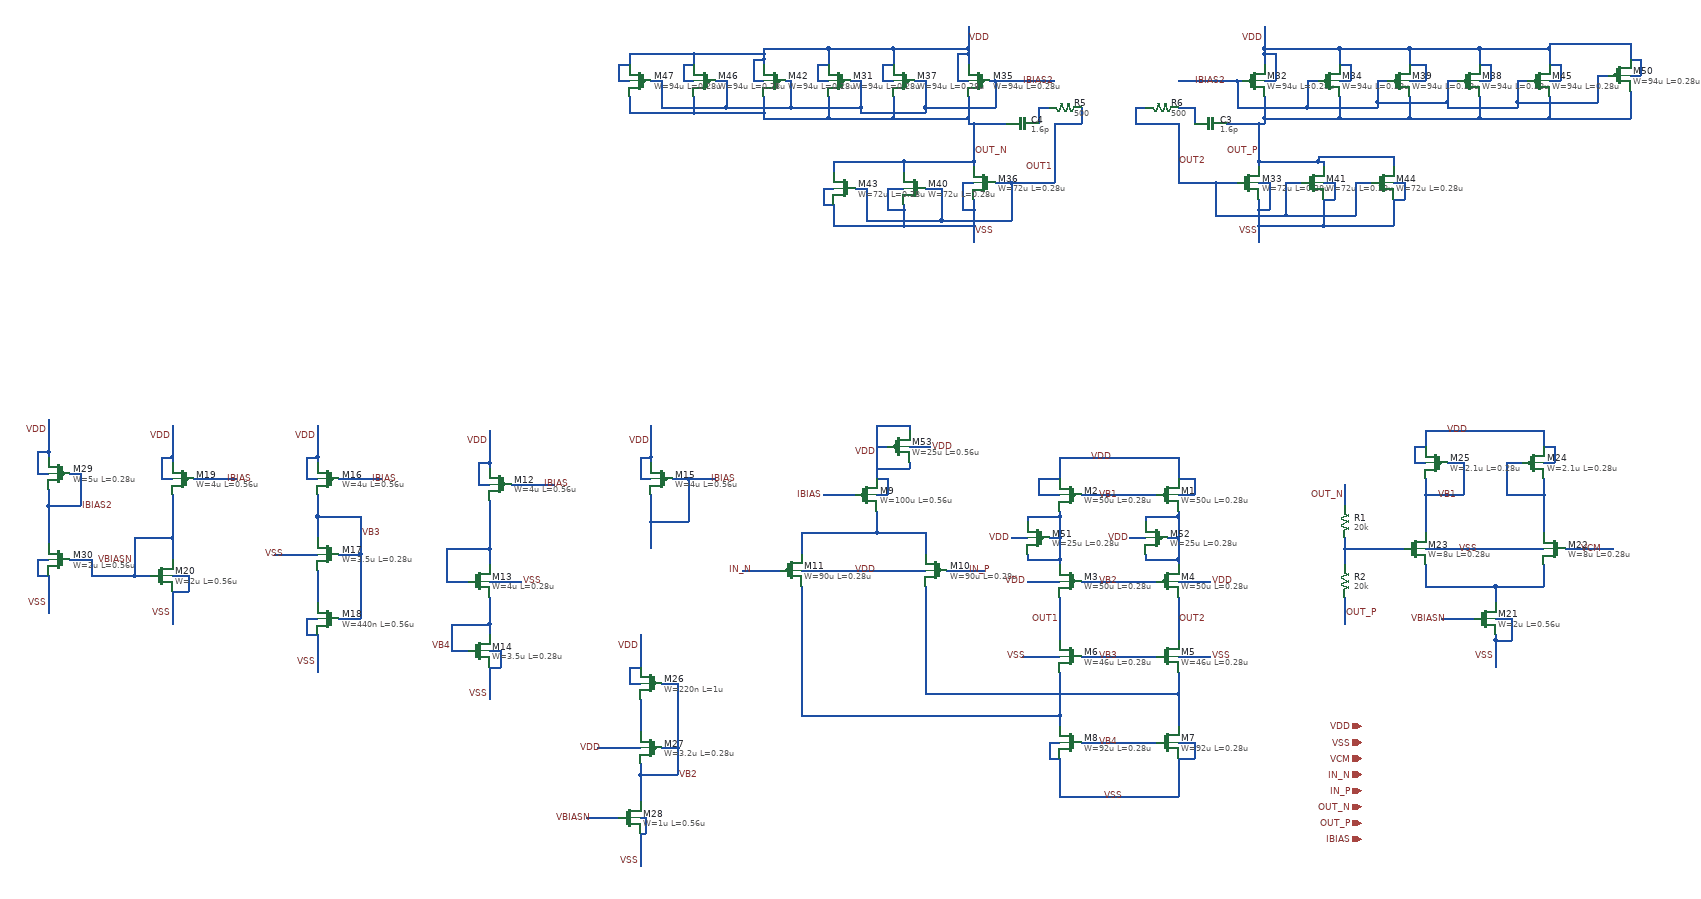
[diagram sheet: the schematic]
v {xschem version=3.1.0 file_version=1.2
}
G {}
K {}
V {}
S {}
E {}
N 80 -230 80 -190 {
lab=VDD}
N 80 -230 300 -230 {
lab=VDD}
N 300 -230 300 -190 {
lab=VDD}
N 300 -40 300 -30 {
lab=#net1}
N 80 -40 80 -30 {
lab=#net2}
N 120 -160 260 -160 {
lab=VB1}
N 120 0 260 0 {
lab=VB2}
N 80 250 80 270 {
lab=#net3}
N 300 210 300 270 {
lab=#net4}
N 80 330 80 400 {
lab=VSS}
N 80 400 300 400 {
lab=VSS}
N 300 330 300 400 {
lab=VSS}
N 120 300 260 300 {
lab=VB4}
N 120 140 260 140 {
lab=VB3}
N 300 140 360 140 {
lab=VSS}
N 300 300 330 300 {
lab=VSS}
N 330 300 330 330 {
lab=VSS}
N 300 330 330 330 {
lab=VSS}
N 10 140 80 140 {
lab=VSS}
N 60 300 80 300 {
lab=VSS}
N 60 300 60 330 {
lab=VSS}
N 60 330 80 330 {
lab=VSS}
N 300 0 360 0 {
lab=VDD}
N 300 -160 330 -160 {
lab=VDD}
N 330 -190 330 -160 {
lab=VDD}
N 300 -190 330 -190 {
lab=VDD}
N 40 -190 80 -190 {
lab=VDD}
N 40 -190 40 -160 {
lab=VDD}
N 40 -160 80 -160 {
lab=VDD}
N 20 0 80 0 {
lab=VDD}
N -400 -90 -400 -50 {
lab=#net5}
N -260 -90 -170 -90 {
lab=#net5}
N -170 -90 -170 -50 {
lab=#net5}
N -260 -130 -260 -90 {
lab=#net5}
N -260 -160 -240 -160 {
lab=VDD}
N -240 -190 -240 -160 {
lab=VDD}
N -260 -190 -240 -190 {
lab=VDD}
N -260 -290 -260 -190 {
lab=VDD}
N -360 -160 -300 -160 {
lab=IBIAS}
N -510 -20 -440 -20 {
lab=IN_N}
N -400 -20 -170 -20 {
lab=VDD}
N -170 210 300 210 {
lab=#net4}
N -400 170 -400 250 {
lab=#net3}
N -400 250 80 250 {
lab=#net3}
N -130 -20 -60 -20 {
lab=IN_P}
N -980 -220 -980 -210 {
lab=VDD}
N -1000 -180 -980 -180 {
lab=VDD}
N -1000 -220 -1000 -180 {
lab=VDD}
N -1000 -220 -980 -220 {
lab=VDD}
N -940 -180 -860 -180 {
lab=IBIAS}
N -980 -150 -980 -60 {
lab=#net6}
N -980 -60 -980 -30 {
lab=#net6}
N -980 0 -920 0 {
lab=VSS}
N -1060 0 -1020 0 {
lab=#net6}
N -1060 -60 -1060 0 {
lab=#net6}
N -1060 -60 -980 -60 {
lab=#net6}
N -980 80 -980 100 {
lab=VB4}
N -1050 130 -1020 130 {
lab=VB4}
N -1050 80 -1050 130 {
lab=VB4}
N -1050 80 -980 80 {
lab=VB4}
N -980 160 -980 220 {
lab=VSS}
N -980 130 -960 130 {
lab=VSS}
N -960 130 -960 160 {
lab=VSS}
N -980 160 -960 160 {
lab=VSS}
N -680 -230 -680 -220 {
lab=VDD}
N -700 -190 -680 -190 {
lab=VDD}
N -700 -230 -700 -190 {
lab=VDD}
N -700 -230 -680 -230 {
lab=VDD}
N -610 -190 -560 -190 {
lab=IBIAS}
N -680 -160 -680 -110 {
lab=IBIAS}
N -680 -110 -610 -110 {
lab=IBIAS}
N -610 -190 -610 -110 {
lab=IBIAS}
N -680 -110 -680 -60 {
lab=IBIAS}
N -1300 -230 -1300 -220 {
lab=VDD}
N -1320 -190 -1300 -190 {
lab=VDD}
N -1320 -230 -1320 -190 {
lab=VDD}
N -1320 -230 -1300 -230 {
lab=VDD}
N -1260 -190 -1180 -190 {
lab=IBIAS}
N -1300 100 -1300 170 {
lab=VSS}
N -1260 70 -1220 70 {
lab=VB3}
N -1300 -20 -1300 40 {
lab=#net7}
N -1260 -50 -1220 -50 {
lab=VB3}
N -1220 -50 -1220 70 {
lab=VB3}
N -1220 -120 -1220 -50 {
lab=VB3}
N -1300 -120 -1220 -120 {
lab=VB3}
N -1300 -160 -1300 -120 {
lab=VB3}
N -1300 -120 -1300 -80 {
lab=VB3}
N -1380 -50 -1300 -50 {
lab=VSS}
N -1320 70 -1300 70 {
lab=VSS}
N -1320 70 -1320 100 {
lab=VSS}
N -1320 100 -1300 100 {
lab=VSS}
N -1570 -230 -1570 -220 {
lab=VDD}
N -1590 -190 -1570 -190 {
lab=VDD}
N -1590 -230 -1590 -190 {
lab=VDD}
N -1590 -230 -1570 -230 {
lab=VDD}
N -1530 -190 -1450 -190 {
lab=IBIAS}
N -1570 -80 -1570 -40 {
lab=VBIASN}
N -1570 20 -1570 80 {
lab=VSS}
N -1570 -10 -1540 -10 {
lab=VSS}
N -1540 -10 -1540 20 {
lab=VSS}
N -1570 20 -1540 20 {
lab=VSS}
N -1640 -10 -1610 -10 {
lab=VBIASN}
N -1640 -80 -1640 -10 {
lab=VBIASN}
N -1640 -80 -1570 -80 {
lab=VBIASN}
N 760 -280 760 -250 {
lab=VDD}
N 760 -280 980 -280 {
lab=VDD}
N 980 -280 980 -250 {
lab=VDD}
N 980 -160 980 -90 {
lab=#net8}
N 760 -160 760 -90 {
lab=VB1}
N 800 -220 830 -220 {
lab=VB1}
N 830 -220 830 -160 {
lab=VB1}
N 760 -160 830 -160 {
lab=VB1}
N 910 -220 940 -220 {
lab=#net8}
N 910 -220 910 -160 {
lab=#net8}
N 910 -160 980 -160 {
lab=#net8}
N 980 -30 980 10 {
lab=#net9}
N 890 10 980 10 {
lab=#net9}
N 760 -30 760 10 {
lab=#net9}
N 890 10 890 40 {
lab=#net9}
N 890 110 890 160 {
lab=VSS}
N 790 70 850 70 {
lab=VBIASN}
N 610 -180 610 -140 {
lab=OUT_N}
N 610 -60 610 -30 {
lab=#net10}
N 610 30 610 80 {
lab=OUT_P}
N 610 -60 720 -60 {
lab=#net10}
N 1020 -60 1110 -60 {
lab=VCM}
N -700 360 -700 410 {
lab=VB2}
N -700 440 -690 440 {
lab=VSS}
N -690 440 -690 470 {
lab=VSS}
N -700 470 -690 470 {
lab=VSS}
N -700 470 -700 530 {
lab=VSS}
N -800 440 -740 440 {
lab=VBIASN}
N -700 220 -700 280 {
lab=#net11}
N -780 310 -700 310 {
lab=VDD}
N -700 100 -700 160 {
lab=VDD}
N -660 190 -630 190 {
lab=VB2}
N -630 310 -630 360 {
lab=VB2}
N -700 360 -630 360 {
lab=VB2}
N -660 310 -630 310 {
lab=VB2}
N -720 190 -700 190 {
lab=VDD}
N -720 160 -720 190 {
lab=VDD}
N -720 160 -700 160 {
lab=VDD}
N 740 -220 760 -220 {
lab=VDD}
N 740 -250 740 -220 {
lab=VDD}
N 740 -250 760 -250 {
lab=VDD}
N 980 -220 1000 -220 {
lab=VDD}
N 1000 -250 1000 -220 {
lab=VDD}
N 980 -250 1000 -250 {
lab=VDD}
N 760 -60 980 -60 {
lab=VSS}
N 890 70 920 70 {
lab=VSS}
N 920 70 920 110 {
lab=VSS}
N 890 110 920 110 {
lab=VSS}
N -1800 -240 -1800 -230 {
lab=VDD}
N -1820 -200 -1800 -200 {
lab=VDD}
N -1820 -240 -1820 -200 {
lab=VDD}
N -1820 -240 -1800 -240 {
lab=VDD}
N -1800 -10 -1800 60 {
lab=VSS}
N -1820 -40 -1800 -40 {
lab=VSS}
N -1820 -40 -1820 -10 {
lab=VSS}
N -1820 -10 -1800 -10 {
lab=VSS}
N -1760 -40 -1720 -40 {
lab=VBIASN}
N -1720 -40 -1720 -10 {
lab=VBIASN}
N -1720 -10 -1640 -10 {
lab=VBIASN}
N -1800 -140 -1800 -70 {
lab=IBIAS2}
N -1760 -200 -1740 -200 {
lab=IBIAS2}
N -1740 -200 -1740 -140 {
lab=IBIAS2}
N -1800 -140 -1740 -140 {
lab=IBIAS2}
N 460 -980 460 -960 {
lab=VDD}
N 460 -930 480 -930 {
lab=VDD}
N 480 -980 480 -930 {
lab=VDD}
N 460 -980 480 -980 {
lab=VDD}
N 410 -930 420 -930 {
lab=IBIAS2}
N 450 -850 460 -850 {
lab=OUT_P}
N 460 -860 460 -850 {
lab=OUT_P}
N 450 -780 450 -770 {
lab=OUT_P}
N 450 -660 450 -630 {
lab=VSS}
N 450 -740 470 -740 {
lab=VSS}
N 470 -740 470 -690 {
lab=VSS}
N 450 -690 470 -690 {
lab=VSS}
N 300 -850 300 -740 {
lab=OUT2}
N 370 -740 410 -740 {
lab=OUT2}
N 540 -930 560 -930 {
lab=IBIAS2}
N 540 -930 540 -880 {
lab=IBIAS2}
N 410 -880 540 -880 {
lab=IBIAS2}
N 410 -930 410 -880 {
lab=IBIAS2}
N 600 -990 600 -960 {
lab=VDD}
N 460 -990 600 -990 {
lab=VDD}
N 600 -930 620 -930 {
lab=VDD}
N 620 -960 620 -930 {
lab=VDD}
N 600 -960 620 -960 {
lab=VDD}
N 600 -900 600 -860 {
lab=OUT_P}
N 460 -860 600 -860 {
lab=OUT_P}
N -90 -980 -90 -960 {
lab=VDD}
N -110 -930 -90 -930 {
lab=VDD}
N -110 -980 -110 -930 {
lab=VDD}
N -110 -980 -90 -980 {
lab=VDD}
N -40 -930 70 -930 {
lab=IBIAS2}
N -80 -850 -20 -850 {
lab=OUT_N}
N -90 -860 -90 -850 {
lab=OUT_N}
N -80 -780 -80 -770 {
lab=OUT_N}
N -80 -660 -80 -630 {
lab=VSS}
N -100 -740 -80 -740 {
lab=VSS}
N -100 -740 -100 -690 {
lab=VSS}
N -100 -690 -80 -690 {
lab=VSS}
N 70 -850 70 -740 {
lab=OUT1}
N -10 -740 70 -740 {
lab=OUT1}
N -190 -930 -170 -930 {
lab=IBIAS2}
N -170 -930 -170 -880 {
lab=IBIAS2}
N -170 -880 -40 -880 {
lab=IBIAS2}
N -40 -930 -40 -880 {
lab=IBIAS2}
N -230 -990 -230 -960 {
lab=VDD}
N -250 -930 -230 -930 {
lab=VDD}
N -250 -960 -250 -930 {
lab=VDD}
N -250 -960 -230 -960 {
lab=VDD}
N -230 -900 -230 -860 {
lab=OUT_N}
N -230 -860 -90 -860 {
lab=OUT_N}
N 220 -880 240 -880 {
lab=OUT2}
N 220 -880 220 -850 {
lab=OUT2}
N 220 -850 300 -850 {
lab=OUT2}
N 330 -880 330 -850 {
lab=#net12}
N 300 -880 330 -880 {
lab=#net12}
N 120 -880 120 -850 {
lab=OUT1}
N 70 -850 120 -850 {
lab=OUT1}
N 40 -880 40 -850 {
lab=#net13}
N 40 -880 60 -880 {
lab=#net13}
N 730 -990 730 -960 {
lab=VDD}
N 600 -990 730 -990 {
lab=VDD}
N 730 -900 730 -860 {
lab=OUT_P}
N 600 -860 730 -860 {
lab=OUT_P}
N 670 -930 690 -930 {
lab=IBIAS2}
N 670 -890 670 -880 {
lab=IBIAS2}
N 540 -880 670 -880 {
lab=IBIAS2}
N 730 -930 760 -930 {
lab=VDD}
N 760 -960 760 -930 {
lab=VDD}
N 730 -960 760 -960 {
lab=VDD}
N -310 -930 -290 -930 {
lab=IBIAS2}
N -290 -880 -290 -870 {
lab=IBIAS2}
N -290 -870 -170 -870 {
lab=IBIAS2}
N -170 -880 -170 -870 {
lab=IBIAS2}
N -350 -990 -350 -960 {
lab=VDD}
N -230 -990 -90 -990 {
lab=VDD}
N -370 -930 -350 -930 {
lab=VDD}
N -370 -960 -370 -930 {
lab=VDD}
N -370 -960 -350 -960 {
lab=VDD}
N -350 -900 -350 -860 {
lab=OUT_N}
N -350 -860 -230 -860 {
lab=OUT_N}
N 500 -740 530 -740 {
lab=OUT2}
N 500 -740 500 -680 {
lab=OUT2}
N 370 -680 500 -680 {
lab=OUT2}
N 370 -740 370 -680 {
lab=OUT2}
N 570 -780 570 -770 {
lab=OUT_P}
N 560 -780 570 -780 {
lab=OUT_P}
N 570 -710 570 -660 {
lab=VSS}
N 450 -660 570 -660 {
lab=VSS}
N 570 -740 590 -740 {
lab=VSS}
N 590 -740 590 -710 {
lab=VSS}
N 570 -710 590 -710 {
lab=VSS}
N -210 -780 -210 -760 {
lab=OUT_N}
N -210 -780 -80 -780 {
lab=OUT_N}
N -210 -690 -210 -660 {
lab=VSS}
N -210 -660 -80 -660 {
lab=VSS}
N -170 -730 -140 -730 {
lab=OUT1}
N -140 -730 -140 -670 {
lab=OUT1}
N -140 -670 -10 -670 {
lab=OUT1}
N -10 -740 -10 -670 {
lab=OUT1}
N -240 -730 -210 -730 {
lab=VSS}
N -240 -730 -240 -690 {
lab=VSS}
N -240 -690 -210 -690 {
lab=VSS}
N -470 -970 -470 -960 {
lab=VDD}
N -470 -990 -350 -990 {
lab=VDD}
N -470 -870 -470 -860 {
lab=OUT_N}
N -470 -860 -350 -860 {
lab=OUT_N}
N -490 -930 -470 -930 {
lab=VDD}
N -490 -970 -490 -930 {
lab=VDD}
N -490 -970 -470 -970 {
lab=VDD}
N -430 -930 -420 -930 {
lab=IBIAS2}
N -420 -930 -420 -880 {
lab=IBIAS2}
N -420 -880 -290 -880 {
lab=IBIAS2}
N 860 -990 860 -960 {
lab=VDD}
N 730 -990 860 -990 {
lab=VDD}
N 860 -930 880 -930 {
lab=VDD}
N 880 -960 880 -930 {
lab=VDD}
N 860 -960 880 -960 {
lab=VDD}
N 800 -930 820 -930 {
lab=IBIAS2}
N 800 -930 800 -890 {
lab=IBIAS2}
N 670 -890 800 -890 {
lab=IBIAS2}
N 860 -900 860 -860 {
lab=OUT_P}
N 730 -860 860 -860 {
lab=OUT_P}
N 700 -790 700 -770 {
lab=OUT_P}
N 560 -790 700 -790 {
lab=OUT_P}
N 560 -790 560 -780 {
lab=OUT_P}
N 630 -740 660 -740 {
lab=OUT2}
N 630 -740 630 -680 {
lab=OUT2}
N 500 -680 630 -680 {
lab=OUT2}
N 570 -660 700 -660 {
lab=VSS}
N 700 -710 700 -660 {
lab=VSS}
N 700 -740 720 -740 {
lab=VSS}
N 720 -740 720 -710 {
lab=VSS}
N 700 -710 720 -710 {
lab=VSS}
N -340 -780 -340 -760 {
lab=OUT_N}
N -340 -780 -210 -780 {
lab=OUT_N}
N -340 -700 -340 -660 {
lab=VSS}
N -340 -660 -210 -660 {
lab=VSS}
N -360 -730 -340 -730 {
lab=VSS}
N -360 -730 -360 -700 {
lab=VSS}
N -360 -700 -340 -700 {
lab=VSS}
N -300 -730 -280 -730 {
lab=OUT1}
N -280 -730 -280 -670 {
lab=OUT1}
N -280 -670 -140 -670 {
lab=OUT1}
N 990 -990 990 -960 {
lab=VDD}
N 860 -990 990 -990 {
lab=VDD}
N 860 -860 990 -860 {
lab=OUT_P}
N 990 -900 990 -860 {
lab=OUT_P}
N 990 -930 1010 -930 {
lab=VDD}
N 1010 -960 1010 -930 {
lab=VDD}
N 990 -960 1010 -960 {
lab=VDD}
N 930 -930 950 -930 {
lab=IBIAS2}
N 930 -890 930 -880 {
lab=IBIAS2}
N 800 -880 930 -880 {
lab=IBIAS2}
N 800 -890 800 -880 {
lab=IBIAS2}
N -600 -980 -600 -960 {
lab=VDD}
N -600 -980 -470 -980 {
lab=VDD}
N -600 -900 -600 -870 {
lab=OUT_N}
N -600 -870 -470 -870 {
lab=OUT_N}
N -540 -880 -420 -880 {
lab=IBIAS2}
N -540 -930 -540 -880 {
lab=IBIAS2}
N -560 -930 -540 -930 {
lab=IBIAS2}
N -620 -930 -600 -930 {
lab=VDD}
N -620 -960 -620 -930 {
lab=VDD}
N -620 -960 -600 -960 {
lab=VDD}
N 1140 -1000 1140 -970 {
lab=VDD}
N 1140 -910 1140 -860 {
lab=OUT_P}
N 1140 -940 1160 -940 {
lab=VDD}
N 1160 -970 1160 -940 {
lab=VDD}
N 1140 -970 1160 -970 {
lab=VDD}
N 1080 -940 1100 -940 {
lab=IBIAS2}
N 1080 -940 1080 -890 {
lab=IBIAS2}
N -720 -980 -720 -960 {
lab=VDD}
N -720 -900 -720 -870 {
lab=OUT_N}
N -660 -930 -660 -880 {
lab=IBIAS2}
N -680 -930 -660 -930 {
lab=IBIAS2}
N -740 -930 -720 -930 {
lab=VDD}
N -740 -960 -740 -930 {
lab=VDD}
N -740 -960 -720 -960 {
lab=VDD}
N -660 -880 -540 -880 {
lab=IBIAS2}
N -720 -870 -600 -870 {
lab=OUT_N}
N -720 -980 -600 -980 {
lab=VDD}
N 990 -1000 1140 -1000 {
lab=VDD}
N 990 -1000 990 -990 {
lab=VDD}
N 990 -860 1140 -860 {
lab=OUT_P}
N 930 -890 1080 -890 {
lab=IBIAS2}
N 60 -80 80 -80 {
lab=#net2}
N 20 -120 20 -110 {
lab=#net2}
N 20 -120 80 -120 {
lab=#net2}
N 20 -50 20 -40 {
lab=#net2}
N 20 -40 80 -40 {
lab=#net2}
N -10 -80 20 -80 {
lab=VDD}
N 280 -80 300 -80 {
lab=#net1}
N 240 -120 240 -110 {
lab=#net1}
N 240 -120 300 -120 {
lab=#net1}
N 240 -50 240 -40 {
lab=#net1}
N 240 -40 300 -40 {
lab=#net1}
N 210 -80 240 -80 {
lab=VDD}
N -400 -90 -260 -90 {
lab=#net5}
N 300 170 300 210 {
lab=#net4}
N 80 170 80 250 {
lab=#net3}
N -980 -280 -980 -220 {
lab=VDD}
N -980 30 -980 80 {
lab=VB4}
N -680 -290 -680 -230 {
lab=VDD}
N -640 -190 -610 -190 {
lab=IBIAS}
N -1300 -290 -1300 -230 {
lab=VDD}
N -1570 -290 -1570 -230 {
lab=VDD}
N -1570 -160 -1570 -80 {
lab=VBIASN}
N 760 -190 760 -160 {
lab=VB1}
N 980 -190 980 -160 {
lab=#net8}
N 760 10 890 10 {
lab=#net9}
N 610 -80 610 -60 {
lab=#net10}
N -700 340 -700 360 {
lab=VB2}
N -630 190 -630 310 {
lab=VB2}
N 890 100 890 110 {
lab=VSS}
N -1800 -300 -1800 -240 {
lab=VDD}
N -1800 -170 -1800 -140 {
lab=IBIAS2}
N 460 -990 460 -980 {
lab=VDD}
N 390 -850 450 -850 {
lab=OUT_P}
N 450 -710 450 -690 {
lab=VSS}
N 300 -930 410 -930 {
lab=IBIAS2}
N 460 -1030 460 -990 {
lab=VDD}
N 460 -900 460 -860 {
lab=OUT_P}
N -90 -990 -90 -980 {
lab=VDD}
N -90 -850 -80 -850 {
lab=OUT_N}
N -80 -710 -80 -690 {
lab=VSS}
N -50 -930 -40 -930 {
lab=IBIAS2}
N -350 -990 -230 -990 {
lab=VDD}
N -90 -1030 -90 -990 {
lab=VDD}
N -90 -900 -90 -860 {
lab=OUT_N}
N 300 -740 370 -740 {
lab=OUT2}
N 450 -850 450 -780 {
lab=OUT_P}
N 450 -690 450 -660 {
lab=VSS}
N -80 -850 -80 -780 {
lab=OUT_N}
N -80 -690 -80 -660 {
lab=VSS}
N -40 -740 -10 -740 {
lab=OUT1}
N -210 -700 -210 -690 {
lab=VSS}
N -470 -980 -470 -970 {
lab=VDD}
N -290 -930 -290 -880 {
lab=IBIAS2}
N 670 -930 670 -890 {
lab=IBIAS2}
N 450 -780 560 -780 {
lab=OUT_P}
N -470 -990 -470 -980 {
lab=VDD}
N -470 -900 -470 -870 {
lab=OUT_N}
N 930 -930 930 -890 {
lab=IBIAS2}
N -400 10 -400 90 {
lab=#net3}
N -170 10 -170 90 {
lab=#net4}
N -170 170 -170 210 {
lab=#net4}
N 80 -120 80 -80 {
lab=#net2}
N 80 -130 80 -120 {
lab=#net2}
N 80 -80 80 -40 {
lab=#net2}
N 300 -120 300 -80 {
lab=#net1}
N 300 -130 300 -120 {
lab=#net1}
N 300 -80 300 -40 {
lab=#net1}
N -200 -290 -200 -280 {
lab=VDD}
N -200 -220 -200 -210 {
lab=VDD}
N -200 -250 -160 -250 {
lab=VDD}
N -260 -250 -240 -250 {
lab=VDD}
N -260 -210 -200 -210 {
lab=VDD}
N -260 -290 -200 -290 {
lab=VDD}
N -400 90 -400 170 {
lab=#net3}
N -170 90 -170 170 {
lab=#net4}
N 300 30 300 110 {
lab=#net14}
N 80 30 80 110 {
lab=OUT1}
C {symbols/pfet_03v3.sym} 280 -160 0 0 {name=M1
L=0.28u
W=50u
nf=1
m=1
ad="'int((nf+1)/2) * W/nf * 0.18u'"
pd="'2*int((nf+1)/2) * (W/nf + 0.18u)'"
as="'int((nf+2)/2) * W/nf * 0.18u'"
ps="'2*int((nf+2)/2) * (W/nf + 0.18u)'"
nrd="'0.18u / W'" nrs="'0.18u / W'"
sa=0 sb=0 sd=0
model=pfet_03v3
spiceprefix=X
}
C {symbols/pfet_03v3.sym} 100 -160 0 1 {name=M2
L=0.28u
W=50u
nf=1
m=1
ad="'int((nf+1)/2) * W/nf * 0.18u'"
pd="'2*int((nf+1)/2) * (W/nf + 0.18u)'"
as="'int((nf+2)/2) * W/nf * 0.18u'"
ps="'2*int((nf+2)/2) * (W/nf + 0.18u)'"
nrd="'0.18u / W'" nrs="'0.18u / W'"
sa=0 sb=0 sd=0
model=pfet_03v3
spiceprefix=X
}
C {symbols/pfet_03v3.sym} 100 0 0 1 {name=M3
L=0.28u
W=50u
nf=1
m=1
ad="'int((nf+1)/2) * W/nf * 0.18u'"
pd="'2*int((nf+1)/2) * (W/nf + 0.18u)'"
as="'int((nf+2)/2) * W/nf * 0.18u'"
ps="'2*int((nf+2)/2) * (W/nf + 0.18u)'"
nrd="'0.18u / W'" nrs="'0.18u / W'"
sa=0 sb=0 sd=0
model=pfet_03v3
spiceprefix=X
}
C {symbols/pfet_03v3.sym} 280 0 0 0 {name=M4
L=0.28u
W=50u
nf=1
m=1
ad="'int((nf+1)/2) * W/nf * 0.18u'"
pd="'2*int((nf+1)/2) * (W/nf + 0.18u)'"
as="'int((nf+2)/2) * W/nf * 0.18u'"
ps="'2*int((nf+2)/2) * (W/nf + 0.18u)'"
nrd="'0.18u / W'" nrs="'0.18u / W'"
sa=0 sb=0 sd=0
model=pfet_03v3
spiceprefix=X
}
C {symbols/nfet_03v3.sym} 280 140 0 0 {name=M5
L=0.28u
W=46u
nf=1
m=1
ad="'int((nf+1)/2) * W/nf * 0.18u'"
pd="'2*int((nf+1)/2) * (W/nf + 0.18u)'"
as="'int((nf+2)/2) * W/nf * 0.18u'"
ps="'2*int((nf+2)/2) * (W/nf + 0.18u)'"
nrd="'0.18u / W'" nrs="'0.18u / W'"
sa=0 sb=0 sd=0
model=nfet_03v3
spiceprefix=X
}
C {symbols/nfet_03v3.sym} 100 140 0 1 {name=M6
L=0.28u
W=46u
nf=1
m=1
ad="'int((nf+1)/2) * W/nf * 0.18u'"
pd="'2*int((nf+1)/2) * (W/nf + 0.18u)'"
as="'int((nf+2)/2) * W/nf * 0.18u'"
ps="'2*int((nf+2)/2) * (W/nf + 0.18u)'"
nrd="'0.18u / W'" nrs="'0.18u / W'"
sa=0 sb=0 sd=0
model=nfet_03v3
spiceprefix=X
}
C {symbols/nfet_03v3.sym} 280 300 0 0 {name=M7
L=0.28u
W=92u
nf=1
m=1
ad="'int((nf+1)/2) * W/nf * 0.18u'"
pd="'2*int((nf+1)/2) * (W/nf + 0.18u)'"
as="'int((nf+2)/2) * W/nf * 0.18u'"
ps="'2*int((nf+2)/2) * (W/nf + 0.18u)'"
nrd="'0.18u / W'" nrs="'0.18u / W'"
sa=0 sb=0 sd=0
model=nfet_03v3
spiceprefix=X
}
C {symbols/nfet_03v3.sym} 100 300 0 1 {name=M8
L=0.28u
W=92u
nf=1
m=1
ad="'int((nf+1)/2) * W/nf * 0.18u'"
pd="'2*int((nf+1)/2) * (W/nf + 0.18u)'"
as="'int((nf+2)/2) * W/nf * 0.18u'"
ps="'2*int((nf+2)/2) * (W/nf + 0.18u)'"
nrd="'0.18u / W'" nrs="'0.18u / W'"
sa=0 sb=0 sd=0
model=nfet_03v3
spiceprefix=X
}
C {symbols/pfet_03v3.sym} -280 -160 0 0 {name=M9
L=0.56u
W=100u
nf=1
m=1
ad="'int((nf+1)/2) * W/nf * 0.18u'"
pd="'2*int((nf+1)/2) * (W/nf + 0.18u)'"
as="'int((nf+2)/2) * W/nf * 0.18u'"
ps="'2*int((nf+2)/2) * (W/nf + 0.18u)'"
nrd="'0.18u / W'" nrs="'0.18u / W'"
sa=0 sb=0 sd=0
model=pfet_03v3
spiceprefix=X
}
C {symbols/pfet_03v3.sym} -150 -20 0 1 {name=M10
L=0.28u
W=90u
nf=1
m=1
ad="'int((nf+1)/2) * W/nf * 0.18u'"
pd="'2*int((nf+1)/2) * (W/nf + 0.18u)'"
as="'int((nf+2)/2) * W/nf * 0.18u'"
ps="'2*int((nf+2)/2) * (W/nf + 0.18u)'"
nrd="'0.18u / W'" nrs="'0.18u / W'"
sa=0 sb=0 sd=0
model=pfet_03v3
spiceprefix=X
}
C {symbols/pfet_03v3.sym} -420 -20 0 0 {name=M11
L=0.28u
W=90u
nf=1
m=1
ad="'int((nf+1)/2) * W/nf * 0.18u'"
pd="'2*int((nf+1)/2) * (W/nf + 0.18u)'"
as="'int((nf+2)/2) * W/nf * 0.18u'"
ps="'2*int((nf+2)/2) * (W/nf + 0.18u)'"
nrd="'0.18u / W'" nrs="'0.18u / W'"
sa=0 sb=0 sd=0
model=pfet_03v3
spiceprefix=X
}
C {devices/lab_wire.sym} 180 -230 0 0 {name=p1 sig_type=std_logic lab=VDD}
C {devices/lab_wire.sym} -260 -240 0 0 {name=p2 sig_type=std_logic lab=VDD}
C {devices/lab_wire.sym} -260 -20 0 0 {name=p3 sig_type=std_logic lab=VDD}
C {devices/lab_wire.sym} 20 0 0 0 {name=p4 sig_type=std_logic lab=VDD}
C {devices/lab_wire.sym} 360 0 0 1 {name=p5 sig_type=std_logic lab=VDD}
C {devices/lab_wire.sym} 200 400 0 0 {name=p6 sig_type=std_logic lab=VSS}
C {devices/lab_wire.sym} 20 140 0 0 {name=p7 sig_type=std_logic lab=VSS}
C {devices/lab_wire.sym} 360 140 0 1 {name=p8 sig_type=std_logic lab=VSS}
C {symbols/pfet_03v3.sym} -960 -180 0 1 {name=M12
L=0.56u
W=4u
nf=1
m=1
ad="'int((nf+1)/2) * W/nf * 0.18u'"
pd="'2*int((nf+1)/2) * (W/nf + 0.18u)'"
as="'int((nf+2)/2) * W/nf * 0.18u'"
ps="'2*int((nf+2)/2) * (W/nf + 0.18u)'"
nrd="'0.18u / W'" nrs="'0.18u / W'"
sa=0 sb=0 sd=0
model=pfet_03v3
spiceprefix=X
}
C {symbols/nfet_03v3.sym} -1000 0 0 0 {name=M13
L=0.28u
W=4u
nf=1
m=1
ad="'int((nf+1)/2) * W/nf * 0.18u'"
pd="'2*int((nf+1)/2) * (W/nf + 0.18u)'"
as="'int((nf+2)/2) * W/nf * 0.18u'"
ps="'2*int((nf+2)/2) * (W/nf + 0.18u)'"
nrd="'0.18u / W'" nrs="'0.18u / W'"
sa=0 sb=0 sd=0
model=nfet_03v3
spiceprefix=X
}
C {symbols/nfet_03v3.sym} -1000 130 0 0 {name=M14
L=0.28u
W=3.5u
nf=1
m=1
ad="'int((nf+1)/2) * W/nf * 0.18u'"
pd="'2*int((nf+1)/2) * (W/nf + 0.18u)'"
as="'int((nf+2)/2) * W/nf * 0.18u'"
ps="'2*int((nf+2)/2) * (W/nf + 0.18u)'"
nrd="'0.18u / W'" nrs="'0.18u / W'"
sa=0 sb=0 sd=0
model=nfet_03v3
spiceprefix=X
}
C {devices/lab_wire.sym} -980 210 0 0 {name=p9 sig_type=std_logic lab=VSS}
C {symbols/pfet_03v3.sym} -660 -190 0 1 {name=M15
L=0.56u
W=4u
nf=1
m=1
ad="'int((nf+1)/2) * W/nf * 0.18u'"
pd="'2*int((nf+1)/2) * (W/nf + 0.18u)'"
as="'int((nf+2)/2) * W/nf * 0.18u'"
ps="'2*int((nf+2)/2) * (W/nf + 0.18u)'"
nrd="'0.18u / W'" nrs="'0.18u / W'"
sa=0 sb=0 sd=0
model=pfet_03v3
spiceprefix=X
}
C {devices/lab_wire.sym} -680 -260 0 0 {name=p10 sig_type=std_logic lab=VDD}
C {devices/lab_wire.sym} -980 -260 0 0 {name=p11 sig_type=std_logic lab=VDD}
C {devices/lab_wire.sym} -920 0 0 1 {name=p12 sig_type=std_logic lab=VSS}
C {devices/lab_wire.sym} -570 -190 0 1 {name=p14 sig_type=std_logic lab=IBIAS}
C {devices/lab_wire.sym} -880 -180 0 1 {name=p15 sig_type=std_logic lab=IBIAS}
C {devices/lab_wire.sym} -360 -160 0 0 {name=p16 sig_type=std_logic lab=IBIAS}
C {devices/lab_wire.sym} -490 -20 0 0 {name=p17 sig_type=std_logic lab=IN_N}
C {devices/lab_wire.sym} -90 -20 0 1 {name=p18 sig_type=std_logic lab=IN_P}
C {devices/lab_wire.sym} 190 -160 0 0 {name=p19 sig_type=std_logic lab=VB1}
C {devices/lab_wire.sym} 190 0 0 0 {name=p20 sig_type=std_logic lab=VB2}
C {devices/lab_wire.sym} 190 140 0 0 {name=p21 sig_type=std_logic lab=VB3}
C {devices/lab_wire.sym} 190 300 0 0 {name=p22 sig_type=std_logic lab=VB4}
C {devices/lab_wire.sym} -1050 120 0 0 {name=p23 sig_type=std_logic lab=VB4}
C {symbols/pfet_03v3.sym} -1280 -190 0 1 {name=M16
L=0.56u
W=4u
nf=1
m=1
ad="'int((nf+1)/2) * W/nf * 0.18u'"
pd="'2*int((nf+1)/2) * (W/nf + 0.18u)'"
as="'int((nf+2)/2) * W/nf * 0.18u'"
ps="'2*int((nf+2)/2) * (W/nf + 0.18u)'"
nrd="'0.18u / W'" nrs="'0.18u / W'"
sa=0 sb=0 sd=0
model=pfet_03v3
spiceprefix=X
}
C {devices/lab_wire.sym} -1300 -270 0 0 {name=p24 sig_type=std_logic lab=VDD}
C {devices/lab_wire.sym} -1200 -190 0 1 {name=p25 sig_type=std_logic lab=IBIAS}
C {symbols/nfet_03v3.sym} -1280 -50 0 1 {name=M17
L=0.28u
W=3.5u
nf=1
m=1
ad="'int((nf+1)/2) * W/nf * 0.18u'"
pd="'2*int((nf+1)/2) * (W/nf + 0.18u)'"
as="'int((nf+2)/2) * W/nf * 0.18u'"
ps="'2*int((nf+2)/2) * (W/nf + 0.18u)'"
nrd="'0.18u / W'" nrs="'0.18u / W'"
sa=0 sb=0 sd=0
model=nfet_03v3
spiceprefix=X
}
C {symbols/nfet_03v3.sym} -1280 70 0 1 {name=M18
L=0.56u
W=440n
nf=1
m=1
ad="'int((nf+1)/2) * W/nf * 0.18u'"
pd="'2*int((nf+1)/2) * (W/nf + 0.18u)'"
as="'int((nf+2)/2) * W/nf * 0.18u'"
ps="'2*int((nf+2)/2) * (W/nf + 0.18u)'"
nrd="'0.18u / W'" nrs="'0.18u / W'"
sa=0 sb=0 sd=0
model=nfet_03v3
spiceprefix=X
}
C {devices/lab_wire.sym} -1360 -50 0 0 {name=p26 sig_type=std_logic lab=VSS}
C {devices/lab_wire.sym} -1220 -90 0 1 {name=p27 sig_type=std_logic lab=VB3}
C {symbols/pfet_03v3.sym} -1550 -190 0 1 {name=M19
L=0.56u
W=4u
nf=1
m=1
ad="'int((nf+1)/2) * W/nf * 0.18u'"
pd="'2*int((nf+1)/2) * (W/nf + 0.18u)'"
as="'int((nf+2)/2) * W/nf * 0.18u'"
ps="'2*int((nf+2)/2) * (W/nf + 0.18u)'"
nrd="'0.18u / W'" nrs="'0.18u / W'"
sa=0 sb=0 sd=0
model=pfet_03v3
spiceprefix=X
}
C {devices/lab_wire.sym} -1570 -270 0 0 {name=p28 sig_type=std_logic lab=VDD}
C {devices/lab_wire.sym} -1470 -190 0 1 {name=p29 sig_type=std_logic lab=IBIAS}
C {symbols/nfet_03v3.sym} -1590 -10 0 0 {name=M20
L=0.56u
W=2u
nf=1
m=1
ad="'int((nf+1)/2) * W/nf * 0.18u'"
pd="'2*int((nf+1)/2) * (W/nf + 0.18u)'"
as="'int((nf+2)/2) * W/nf * 0.18u'"
ps="'2*int((nf+2)/2) * (W/nf + 0.18u)'"
nrd="'0.18u / W'" nrs="'0.18u / W'"
sa=0 sb=0 sd=0
model=nfet_03v3
spiceprefix=X
}
C {devices/lab_wire.sym} -1640 -40 0 0 {name=p30 sig_type=std_logic lab=VBIASN}
C {symbols/nfet_03v3.sym} 870 70 0 0 {name=M21
L=0.56u
W=2u
nf=1
m=1
ad="'int((nf+1)/2) * W/nf * 0.18u'"
pd="'2*int((nf+1)/2) * (W/nf + 0.18u)'"
as="'int((nf+2)/2) * W/nf * 0.18u'"
ps="'2*int((nf+2)/2) * (W/nf + 0.18u)'"
nrd="'0.18u / W'" nrs="'0.18u / W'"
sa=0 sb=0 sd=0
model=nfet_03v3
spiceprefix=X
}
C {symbols/nfet_03v3.sym} 1000 -60 0 1 {name=M22
L=0.28u
W=8u
nf=1
m=1
ad="'int((nf+1)/2) * W/nf * 0.18u'"
pd="'2*int((nf+1)/2) * (W/nf + 0.18u)'"
as="'int((nf+2)/2) * W/nf * 0.18u'"
ps="'2*int((nf+2)/2) * (W/nf + 0.18u)'"
nrd="'0.18u / W'" nrs="'0.18u / W'"
sa=0 sb=0 sd=0
model=nfet_03v3
spiceprefix=X
}
C {symbols/nfet_03v3.sym} 740 -60 0 0 {name=M23
L=0.28u
W=8u
nf=1
m=1
ad="'int((nf+1)/2) * W/nf * 0.18u'"
pd="'2*int((nf+1)/2) * (W/nf + 0.18u)'"
as="'int((nf+2)/2) * W/nf * 0.18u'"
ps="'2*int((nf+2)/2) * (W/nf + 0.18u)'"
nrd="'0.18u / W'" nrs="'0.18u / W'"
sa=0 sb=0 sd=0
model=nfet_03v3
spiceprefix=X
}
C {symbols/pfet_03v3.sym} 960 -220 0 0 {name=M24
L=0.28u
W=2.1u
nf=1
m=1
ad="'int((nf+1)/2) * W/nf * 0.18u'"
pd="'2*int((nf+1)/2) * (W/nf + 0.18u)'"
as="'int((nf+2)/2) * W/nf * 0.18u'"
ps="'2*int((nf+2)/2) * (W/nf + 0.18u)'"
nrd="'0.18u / W'" nrs="'0.18u / W'"
sa=0 sb=0 sd=0
model=pfet_03v3
spiceprefix=X
}
C {symbols/pfet_03v3.sym} 780 -220 0 1 {name=M25
L=0.28u
W=2.1u
nf=1
m=1
ad="'int((nf+1)/2) * W/nf * 0.18u'"
pd="'2*int((nf+1)/2) * (W/nf + 0.18u)'"
as="'int((nf+2)/2) * W/nf * 0.18u'"
ps="'2*int((nf+2)/2) * (W/nf + 0.18u)'"
nrd="'0.18u / W'" nrs="'0.18u / W'"
sa=0 sb=0 sd=0
model=pfet_03v3
spiceprefix=X
}
C {devices/lab_wire.sym} 800 70 0 0 {name=p31 sig_type=std_logic lab=VBIASN}
C {devices/res.sym} 610 -110 0 0 {name=R1
value=20k
footprint=1206
device=resistor
m=1}
C {devices/res.sym} 610 0 0 0 {name=R2
value=20k
footprint=1206
device=resistor
m=1}
C {devices/lab_wire.sym} 840 -280 0 0 {name=p32 sig_type=std_logic lab=VDD}
C {devices/lab_wire.sym} 890 140 0 0 {name=p33 sig_type=std_logic lab=VSS}
C {devices/lab_wire.sym} 80 70 0 0 {name=p34 sig_type=std_logic lab=OUT1}
C {devices/lab_wire.sym} 300 70 0 1 {name=p35 sig_type=std_logic lab=OUT2}
C {devices/lab_wire.sym} 610 -160 0 0 {name=p36 sig_type=std_logic lab=OUT_N}
C {devices/lab_wire.sym} 610 60 0 1 {name=p37 sig_type=std_logic lab=OUT_P}
C {devices/lab_wire.sym} 820 -160 0 0 {name=p38 sig_type=std_logic lab=VB1}
C {symbols/pfet_03v3.sym} -680 190 0 1 {name=M26
L=1u
W=220n
nf=1
m=1
ad="'int((nf+1)/2) * W/nf * 0.18u'"
pd="'2*int((nf+1)/2) * (W/nf + 0.18u)'"
as="'int((nf+2)/2) * W/nf * 0.18u'"
ps="'2*int((nf+2)/2) * (W/nf + 0.18u)'"
nrd="'0.18u / W'" nrs="'0.18u / W'"
sa=0 sb=0 sd=0
model=pfet_03v3
spiceprefix=X
}
C {symbols/pfet_03v3.sym} -680 310 0 1 {name=M27
L=0.28u
W=3.2u
nf=1
m=1
ad="'int((nf+1)/2) * W/nf * 0.18u'"
pd="'2*int((nf+1)/2) * (W/nf + 0.18u)'"
as="'int((nf+2)/2) * W/nf * 0.18u'"
ps="'2*int((nf+2)/2) * (W/nf + 0.18u)'"
nrd="'0.18u / W'" nrs="'0.18u / W'"
sa=0 sb=0 sd=0
model=pfet_03v3
spiceprefix=X
}
C {symbols/nfet_03v3.sym} -720 440 0 0 {name=M28
L=0.56u
W=1u
nf=1
m=1
ad="'int((nf+1)/2) * W/nf * 0.18u'"
pd="'2*int((nf+1)/2) * (W/nf + 0.18u)'"
as="'int((nf+2)/2) * W/nf * 0.18u'"
ps="'2*int((nf+2)/2) * (W/nf + 0.18u)'"
nrd="'0.18u / W'" nrs="'0.18u / W'"
sa=0 sb=0 sd=0
model=nfet_03v3
spiceprefix=X
}
C {devices/lab_wire.sym} -700 120 0 0 {name=p39 sig_type=std_logic lab=VDD}
C {devices/lab_wire.sym} -770 310 0 0 {name=p40 sig_type=std_logic lab=VDD}
C {devices/lab_wire.sym} -700 520 0 0 {name=p41 sig_type=std_logic lab=VSS}
C {devices/lab_wire.sym} -790 440 0 0 {name=p42 sig_type=std_logic lab=VBIASN}
C {devices/lab_wire.sym} -630 360 0 1 {name=p43 sig_type=std_logic lab=VB2}
C {devices/lab_wire.sym} 1090 -60 0 0 {name=p51 sig_type=std_logic lab=VCM}
C {devices/lab_wire.sym} 860 -60 0 0 {name=p47 sig_type=std_logic lab=VSS}
C {devices/lab_wire.sym} -1300 150 0 0 {name=p48 sig_type=std_logic lab=VSS}
C {devices/lab_wire.sym} -1570 60 0 0 {name=p52 sig_type=std_logic lab=VSS}
C {symbols/pfet_03v3.sym} -1780 -200 0 1 {name=M29
L=0.28u
W=5u
nf=1
m=1
ad="'int((nf+1)/2) * W/nf * 0.18u'"
pd="'2*int((nf+1)/2) * (W/nf + 0.18u)'"
as="'int((nf+2)/2) * W/nf * 0.18u'"
ps="'2*int((nf+2)/2) * (W/nf + 0.18u)'"
nrd="'0.18u / W'" nrs="'0.18u / W'"
sa=0 sb=0 sd=0
model=pfet_03v3
spiceprefix=X
}
C {devices/lab_wire.sym} -1800 -280 0 0 {name=p53 sig_type=std_logic lab=VDD}
C {symbols/nfet_03v3.sym} -1780 -40 0 1 {name=M30
L=0.56u
W=2u
nf=1
m=1
ad="'int((nf+1)/2) * W/nf * 0.18u'"
pd="'2*int((nf+1)/2) * (W/nf + 0.18u)'"
as="'int((nf+2)/2) * W/nf * 0.18u'"
ps="'2*int((nf+2)/2) * (W/nf + 0.18u)'"
nrd="'0.18u / W'" nrs="'0.18u / W'"
sa=0 sb=0 sd=0
model=nfet_03v3
spiceprefix=X
}
C {devices/lab_wire.sym} -1740 -140 0 1 {name=p54 sig_type=std_logic lab=IBIAS2}
C {symbols/pfet_03v3.sym} 440 -930 0 0 {name=M32
L=0.28u
W=94u
nf=1
m=1
ad="'int((nf+1)/2) * W/nf * 0.18u'"
pd="'2*int((nf+1)/2) * (W/nf + 0.18u)'"
as="'int((nf+2)/2) * W/nf * 0.18u'"
ps="'2*int((nf+2)/2) * (W/nf + 0.18u)'"
nrd="'0.18u / W'" nrs="'0.18u / W'"
sa=0 sb=0 sd=0
model=pfet_03v3
spiceprefix=X
}
C {symbols/nfet_03v3.sym} 430 -740 0 0 {name=M33
L=0.28u
W=72u
nf=1
m=1
ad="'int((nf+1)/2) * W/nf * 0.18u'"
pd="'2*int((nf+1)/2) * (W/nf + 0.18u)'"
as="'int((nf+2)/2) * W/nf * 0.18u'"
ps="'2*int((nf+2)/2) * (W/nf + 0.18u)'"
nrd="'0.18u / W'" nrs="'0.18u / W'"
sa=0 sb=0 sd=0
model=nfet_03v3
spiceprefix=X
}
C {devices/capa.sym} 360 -850 1 0 {name=C3
m=1
value=1.6p
footprint=1206
device="ceramic capacitor"}
C {symbols/pfet_03v3.sym} 580 -930 0 0 {name=M34
L=0.28u
W=94u
nf=1
m=1
ad="'int((nf+1)/2) * W/nf * 0.18u'"
pd="'2*int((nf+1)/2) * (W/nf + 0.18u)'"
as="'int((nf+2)/2) * W/nf * 0.18u'"
ps="'2*int((nf+2)/2) * (W/nf + 0.18u)'"
nrd="'0.18u / W'" nrs="'0.18u / W'"
sa=0 sb=0 sd=0
model=pfet_03v3
spiceprefix=X
}
C {devices/lab_wire.sym} 460 -1010 0 0 {name=p55 sig_type=std_logic lab=VDD}
C {devices/lab_wire.sym} 450 -650 0 0 {name=p56 sig_type=std_logic lab=VSS}
C {symbols/pfet_03v3.sym} -70 -930 0 1 {name=M35
L=0.28u
W=94u
nf=1
m=1
ad="'int((nf+1)/2) * W/nf * 0.18u'"
pd="'2*int((nf+1)/2) * (W/nf + 0.18u)'"
as="'int((nf+2)/2) * W/nf * 0.18u'"
ps="'2*int((nf+2)/2) * (W/nf + 0.18u)'"
nrd="'0.18u / W'" nrs="'0.18u / W'"
sa=0 sb=0 sd=0
model=pfet_03v3
spiceprefix=X
}
C {symbols/nfet_03v3.sym} -60 -740 0 1 {name=M36
L=0.28u
W=72u
nf=1
m=1
ad="'int((nf+1)/2) * W/nf * 0.18u'"
pd="'2*int((nf+1)/2) * (W/nf + 0.18u)'"
as="'int((nf+2)/2) * W/nf * 0.18u'"
ps="'2*int((nf+2)/2) * (W/nf + 0.18u)'"
nrd="'0.18u / W'" nrs="'0.18u / W'"
sa=0 sb=0 sd=0
model=nfet_03v3
spiceprefix=X
}
C {devices/capa.sym} 10 -850 3 1 {name=C4
m=1
value=1.6p
footprint=1206
device="ceramic capacitor"}
C {symbols/pfet_03v3.sym} -210 -930 0 1 {name=M37
L=0.28u
W=94u
nf=1
m=1
ad="'int((nf+1)/2) * W/nf * 0.18u'"
pd="'2*int((nf+1)/2) * (W/nf + 0.18u)'"
as="'int((nf+2)/2) * W/nf * 0.18u'"
ps="'2*int((nf+2)/2) * (W/nf + 0.18u)'"
nrd="'0.18u / W'" nrs="'0.18u / W'"
sa=0 sb=0 sd=0
model=pfet_03v3
spiceprefix=X
}
C {devices/lab_wire.sym} -90 -1010 0 1 {name=p57 sig_type=std_logic lab=VDD}
C {devices/lab_wire.sym} -80 -650 0 1 {name=p58 sig_type=std_logic lab=VSS}
C {devices/res.sym} 90 -880 1 0 {name=R5
value=500
footprint=1206
device=resistor
m=1}
C {devices/res.sym} 270 -880 1 0 {name=R6
value=500
footprint=1206
device=resistor
m=1}
C {symbols/nfet_03v3.sym} -190 -730 0 1 {name=M40
L=0.28u
W=72u
nf=1
m=1
ad="'int((nf+1)/2) * W/nf * 0.18u'"
pd="'2*int((nf+1)/2) * (W/nf + 0.18u)'"
as="'int((nf+2)/2) * W/nf * 0.18u'"
ps="'2*int((nf+2)/2) * (W/nf + 0.18u)'"
nrd="'0.18u / W'" nrs="'0.18u / W'"
sa=0 sb=0 sd=0
model=nfet_03v3
spiceprefix=X
}
C {symbols/nfet_03v3.sym} 550 -740 0 0 {name=M41
L=0.28u
W=72u
nf=1
m=1
ad="'int((nf+1)/2) * W/nf * 0.18u'"
pd="'2*int((nf+1)/2) * (W/nf + 0.18u)'"
as="'int((nf+2)/2) * W/nf * 0.18u'"
ps="'2*int((nf+2)/2) * (W/nf + 0.18u)'"
nrd="'0.18u / W'" nrs="'0.18u / W'"
sa=0 sb=0 sd=0
model=nfet_03v3
spiceprefix=X
}
C {devices/lab_wire.sym} -80 -800 0 1 {name=p61 sig_type=std_logic lab=OUT_N
}
C {devices/lab_wire.sym} 450 -800 0 0 {name=p62 sig_type=std_logic lab=OUT_P
}
C {devices/lab_wire.sym} 10 -930 0 1 {name=p63 sig_type=std_logic lab=IBIAS2}
C {devices/lab_wire.sym} 330 -930 0 1 {name=p64 sig_type=std_logic lab=IBIAS2}
C {devices/lab_wire.sym} 70 -770 0 0 {name=p59 sig_type=std_logic lab=OUT1}
C {devices/lab_wire.sym} 300 -780 0 1 {name=p60 sig_type=std_logic lab=OUT2}
C {symbols/pfet_03v3.sym} -330 -930 0 1 {name=M31
L=0.28u
W=94u
nf=1
m=1
ad="'int((nf+1)/2) * W/nf * 0.18u'"
pd="'2*int((nf+1)/2) * (W/nf + 0.18u)'"
as="'int((nf+2)/2) * W/nf * 0.18u'"
ps="'2*int((nf+2)/2) * (W/nf + 0.18u)'"
nrd="'0.18u / W'" nrs="'0.18u / W'"
sa=0 sb=0 sd=0
model=pfet_03v3
spiceprefix=X
}
C {symbols/pfet_03v3.sym} 710 -930 0 0 {name=M39
L=0.28u
W=94u
nf=1
m=1
ad="'int((nf+1)/2) * W/nf * 0.18u'"
pd="'2*int((nf+1)/2) * (W/nf + 0.18u)'"
as="'int((nf+2)/2) * W/nf * 0.18u'"
ps="'2*int((nf+2)/2) * (W/nf + 0.18u)'"
nrd="'0.18u / W'" nrs="'0.18u / W'"
sa=0 sb=0 sd=0
model=pfet_03v3
spiceprefix=X
}
C {devices/lab_wire.sym} -1800 40 0 0 {name=p67 sig_type=std_logic lab=VSS}
C {devices/iopin.sym} 640 270 0 0 {name=p65 lab=VDD}
C {devices/iopin.sym} 640 300 0 0 {name=p66 lab=VSS}
C {devices/iopin.sym} 640 330 0 0 {name=p68 lab=VCM}
C {devices/iopin.sym} 640 360 0 0 {name=p69 lab=IN_N}
C {devices/iopin.sym} 640 390 0 0 {name=p70 lab=IN_P}
C {devices/iopin.sym} 640 420 0 0 {name=p71 lab=OUT_N}
C {devices/iopin.sym} 640 450 0 0 {name=p72 lab=OUT_P}
C {devices/iopin.sym} 640 480 0 0 {name=p73 lab=IBIAS}
C {symbols/pfet_03v3.sym} 840 -930 0 0 {name=M38
L=0.28u
W=94u
nf=1
m=1
ad="'int((nf+1)/2) * W/nf * 0.18u'"
pd="'2*int((nf+1)/2) * (W/nf + 0.18u)'"
as="'int((nf+2)/2) * W/nf * 0.18u'"
ps="'2*int((nf+2)/2) * (W/nf + 0.18u)'"
nrd="'0.18u / W'" nrs="'0.18u / W'"
sa=0 sb=0 sd=0
model=pfet_03v3
spiceprefix=X
}
C {symbols/pfet_03v3.sym} -450 -930 0 1 {name=M42
L=0.28u
W=94u
nf=1
m=1
ad="'int((nf+1)/2) * W/nf * 0.18u'"
pd="'2*int((nf+1)/2) * (W/nf + 0.18u)'"
as="'int((nf+2)/2) * W/nf * 0.18u'"
ps="'2*int((nf+2)/2) * (W/nf + 0.18u)'"
nrd="'0.18u / W'" nrs="'0.18u / W'"
sa=0 sb=0 sd=0
model=pfet_03v3
spiceprefix=X
}
C {symbols/nfet_03v3.sym} -320 -730 0 1 {name=M43
L=0.28u
W=72u
nf=1
m=1
ad="'int((nf+1)/2) * W/nf * 0.18u'"
pd="'2*int((nf+1)/2) * (W/nf + 0.18u)'"
as="'int((nf+2)/2) * W/nf * 0.18u'"
ps="'2*int((nf+2)/2) * (W/nf + 0.18u)'"
nrd="'0.18u / W'" nrs="'0.18u / W'"
sa=0 sb=0 sd=0
model=nfet_03v3
spiceprefix=X
}
C {symbols/nfet_03v3.sym} 680 -740 0 0 {name=M44
L=0.28u
W=72u
nf=1
m=1
ad="'int((nf+1)/2) * W/nf * 0.18u'"
pd="'2*int((nf+1)/2) * (W/nf + 0.18u)'"
as="'int((nf+2)/2) * W/nf * 0.18u'"
ps="'2*int((nf+2)/2) * (W/nf + 0.18u)'"
nrd="'0.18u / W'" nrs="'0.18u / W'"
sa=0 sb=0 sd=0
model=nfet_03v3
spiceprefix=X
}
C {symbols/pfet_03v3.sym} 970 -930 0 0 {name=M45
L=0.28u
W=94u
nf=1
m=1
ad="'int((nf+1)/2) * W/nf * 0.18u'"
pd="'2*int((nf+1)/2) * (W/nf + 0.18u)'"
as="'int((nf+2)/2) * W/nf * 0.18u'"
ps="'2*int((nf+2)/2) * (W/nf + 0.18u)'"
nrd="'0.18u / W'" nrs="'0.18u / W'"
sa=0 sb=0 sd=0
model=pfet_03v3
spiceprefix=X
}
C {symbols/pfet_03v3.sym} -580 -930 0 1 {name=M46
L=0.28u
W=94u
nf=1
m=1
ad="'int((nf+1)/2) * W/nf * 0.18u'"
pd="'2*int((nf+1)/2) * (W/nf + 0.18u)'"
as="'int((nf+2)/2) * W/nf * 0.18u'"
ps="'2*int((nf+2)/2) * (W/nf + 0.18u)'"
nrd="'0.18u / W'" nrs="'0.18u / W'"
sa=0 sb=0 sd=0
model=pfet_03v3
spiceprefix=X
}
C {symbols/pfet_03v3.sym} -700 -930 0 1 {name=M47
L=0.28u
W=94u
nf=1
m=1
ad="'int((nf+1)/2) * W/nf * 0.18u'"
pd="'2*int((nf+1)/2) * (W/nf + 0.18u)'"
as="'int((nf+2)/2) * W/nf * 0.18u'"
ps="'2*int((nf+2)/2) * (W/nf + 0.18u)'"
nrd="'0.18u / W'" nrs="'0.18u / W'"
sa=0 sb=0 sd=0
model=pfet_03v3
spiceprefix=X
}
C {symbols/pfet_03v3.sym} 1120 -940 0 0 {name=M50
L=0.28u
W=94u
nf=1
m=1
ad="'int((nf+1)/2) * W/nf * 0.18u'"
pd="'2*int((nf+1)/2) * (W/nf + 0.18u)'"
as="'int((nf+2)/2) * W/nf * 0.18u'"
ps="'2*int((nf+2)/2) * (W/nf + 0.18u)'"
nrd="'0.18u / W'" nrs="'0.18u / W'"
sa=0 sb=0 sd=0
model=pfet_03v3
spiceprefix=X
}
C {symbols/pfet_03v3.sym} 40 -80 0 1 {name=M51
L=0.28u
W=25u
nf=1
m=1
ad="'int((nf+1)/2) * W/nf * 0.18u'"
pd="'2*int((nf+1)/2) * (W/nf + 0.18u)'"
as="'int((nf+2)/2) * W/nf * 0.18u'"
ps="'2*int((nf+2)/2) * (W/nf + 0.18u)'"
nrd="'0.18u / W'" nrs="'0.18u / W'"
sa=0 sb=0 sd=0
model=pfet_03v3
spiceprefix=X
}
C {devices/lab_wire.sym} -10 -80 0 0 {name=p45 sig_type=std_logic lab=VDD}
C {symbols/pfet_03v3.sym} 260 -80 0 1 {name=M52
L=0.28u
W=25u
nf=1
m=1
ad="'int((nf+1)/2) * W/nf * 0.18u'"
pd="'2*int((nf+1)/2) * (W/nf + 0.18u)'"
as="'int((nf+2)/2) * W/nf * 0.18u'"
ps="'2*int((nf+2)/2) * (W/nf + 0.18u)'"
nrd="'0.18u / W'" nrs="'0.18u / W'"
sa=0 sb=0 sd=0
model=pfet_03v3
spiceprefix=X
}
C {devices/lab_wire.sym} 210 -80 0 0 {name=p46 sig_type=std_logic lab=VDD}
C {symbols/pfet_03v3.sym} -220 -250 0 0 {name=M53
L=0.56u
W=25u
nf=1
m=1
ad="'int((nf+1)/2) * W/nf * 0.18u'"
pd="'2*int((nf+1)/2) * (W/nf + 0.18u)'"
as="'int((nf+2)/2) * W/nf * 0.18u'"
ps="'2*int((nf+2)/2) * (W/nf + 0.18u)'"
nrd="'0.18u / W'" nrs="'0.18u / W'"
sa=0 sb=0 sd=0
model=pfet_03v3
spiceprefix=X
}
C {devices/lab_wire.sym} -160 -250 0 1 {name=p49 sig_type=std_logic lab=VDD}
